# Generated deterministically by seda-macro-lef-normalizer-v1; recipe orfs-asap7-fakeram-m4-v1.
VERSION 5.8 ;
BUSBITCHARS "[]" ;
DIVIDERCHAR "/" ;

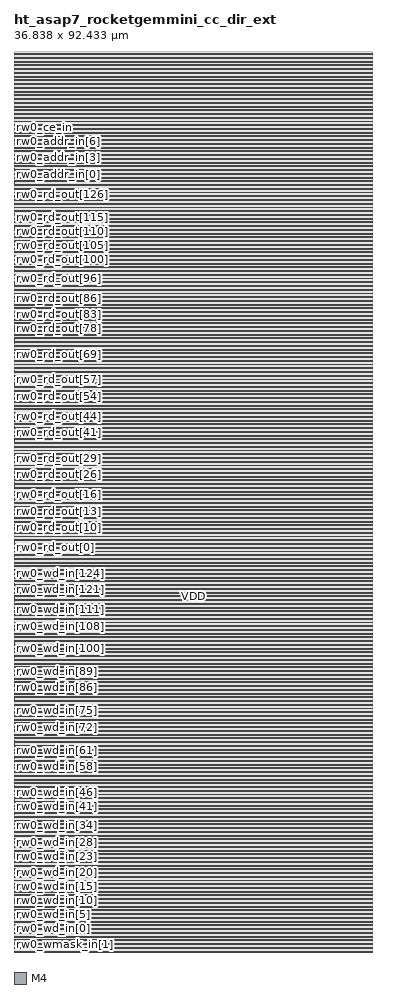
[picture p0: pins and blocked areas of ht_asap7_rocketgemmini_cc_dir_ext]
MACRO ht_asap7_rocketgemmini_cc_dir_ext
  FOREIGN ht_asap7_rocketgemmini_cc_dir_ext 0 0 ;
  CLASS BLOCK ;
  ORIGIN 0 0 ;
  SIZE 36.838 BY 92.433 ;
  SYMMETRY X Y R90 ;
  PIN rw0_wmask_in[0]
    DIRECTION INPUT ;
    USE SIGNAL ;
    SHAPE ABUTMENT ;
    PORT
      LAYER M4 ;
      RECT 0 0.048 0.024 0.072 ;
    END
  END rw0_wmask_in[0]
  PIN rw0_wmask_in[1]
    DIRECTION INPUT ;
    USE SIGNAL ;
    SHAPE ABUTMENT ;
    PORT
      LAYER M4 ;
      RECT 0 0.336 0.024 0.36 ;
    END
  END rw0_wmask_in[1]
  PIN rw0_wmask_in[2]
    DIRECTION INPUT ;
    USE SIGNAL ;
    SHAPE ABUTMENT ;
    PORT
      LAYER M4 ;
      RECT 0 0.624 0.024 0.648 ;
    END
  END rw0_wmask_in[2]
  PIN rw0_wmask_in[3]
    DIRECTION INPUT ;
    USE SIGNAL ;
    SHAPE ABUTMENT ;
    PORT
      LAYER M4 ;
      RECT 0 0.912 0.024 0.936 ;
    END
  END rw0_wmask_in[3]
  PIN rw0_wmask_in[4]
    DIRECTION INPUT ;
    USE SIGNAL ;
    SHAPE ABUTMENT ;
    PORT
      LAYER M4 ;
      RECT 0 1.2 0.024 1.224 ;
    END
  END rw0_wmask_in[4]
  PIN rw0_wmask_in[5]
    DIRECTION INPUT ;
    USE SIGNAL ;
    SHAPE ABUTMENT ;
    PORT
      LAYER M4 ;
      RECT 0 1.488 0.024 1.512 ;
    END
  END rw0_wmask_in[5]
  PIN rw0_wmask_in[6]
    DIRECTION INPUT ;
    USE SIGNAL ;
    SHAPE ABUTMENT ;
    PORT
      LAYER M4 ;
      RECT 0 1.776 0.024 1.8 ;
    END
  END rw0_wmask_in[6]
  PIN rw0_wmask_in[7]
    DIRECTION INPUT ;
    USE SIGNAL ;
    SHAPE ABUTMENT ;
    PORT
      LAYER M4 ;
      RECT 0 2.064 0.024 2.088 ;
    END
  END rw0_wmask_in[7]
  PIN rw0_wd_in[0]
    DIRECTION INPUT ;
    USE SIGNAL ;
    SHAPE ABUTMENT ;
    PORT
      LAYER M4 ;
      RECT 0 2.352 0.024 2.376 ;
    END
  END rw0_wd_in[0]
  PIN rw0_wd_in[1]
    DIRECTION INPUT ;
    USE SIGNAL ;
    SHAPE ABUTMENT ;
    PORT
      LAYER M4 ;
      RECT 0 2.64 0.024 2.664 ;
    END
  END rw0_wd_in[1]
  PIN rw0_wd_in[2]
    DIRECTION INPUT ;
    USE SIGNAL ;
    SHAPE ABUTMENT ;
    PORT
      LAYER M4 ;
      RECT 0 2.928 0.024 2.952 ;
    END
  END rw0_wd_in[2]
  PIN rw0_wd_in[3]
    DIRECTION INPUT ;
    USE SIGNAL ;
    SHAPE ABUTMENT ;
    PORT
      LAYER M4 ;
      RECT 0 3.216 0.024 3.24 ;
    END
  END rw0_wd_in[3]
  PIN rw0_wd_in[4]
    DIRECTION INPUT ;
    USE SIGNAL ;
    SHAPE ABUTMENT ;
    PORT
      LAYER M4 ;
      RECT 0 3.504 0.024 3.528 ;
    END
  END rw0_wd_in[4]
  PIN rw0_wd_in[5]
    DIRECTION INPUT ;
    USE SIGNAL ;
    SHAPE ABUTMENT ;
    PORT
      LAYER M4 ;
      RECT 0 3.792 0.024 3.816 ;
    END
  END rw0_wd_in[5]
  PIN rw0_wd_in[6]
    DIRECTION INPUT ;
    USE SIGNAL ;
    SHAPE ABUTMENT ;
    PORT
      LAYER M4 ;
      RECT 0 4.08 0.024 4.104 ;
    END
  END rw0_wd_in[6]
  PIN rw0_wd_in[7]
    DIRECTION INPUT ;
    USE SIGNAL ;
    SHAPE ABUTMENT ;
    PORT
      LAYER M4 ;
      RECT 0 4.368 0.024 4.392 ;
    END
  END rw0_wd_in[7]
  PIN rw0_wd_in[8]
    DIRECTION INPUT ;
    USE SIGNAL ;
    SHAPE ABUTMENT ;
    PORT
      LAYER M4 ;
      RECT 0 4.656 0.024 4.68 ;
    END
  END rw0_wd_in[8]
  PIN rw0_wd_in[9]
    DIRECTION INPUT ;
    USE SIGNAL ;
    SHAPE ABUTMENT ;
    PORT
      LAYER M4 ;
      RECT 0 4.944 0.024 4.968 ;
    END
  END rw0_wd_in[9]
  PIN rw0_wd_in[10]
    DIRECTION INPUT ;
    USE SIGNAL ;
    SHAPE ABUTMENT ;
    PORT
      LAYER M4 ;
      RECT 0 5.232 0.024 5.256 ;
    END
  END rw0_wd_in[10]
  PIN rw0_wd_in[11]
    DIRECTION INPUT ;
    USE SIGNAL ;
    SHAPE ABUTMENT ;
    PORT
      LAYER M4 ;
      RECT 0 5.52 0.024 5.544 ;
    END
  END rw0_wd_in[11]
  PIN rw0_wd_in[12]
    DIRECTION INPUT ;
    USE SIGNAL ;
    SHAPE ABUTMENT ;
    PORT
      LAYER M4 ;
      RECT 0 5.808 0.024 5.832 ;
    END
  END rw0_wd_in[12]
  PIN rw0_wd_in[13]
    DIRECTION INPUT ;
    USE SIGNAL ;
    SHAPE ABUTMENT ;
    PORT
      LAYER M4 ;
      RECT 0 6.096 0.024 6.12 ;
    END
  END rw0_wd_in[13]
  PIN rw0_wd_in[14]
    DIRECTION INPUT ;
    USE SIGNAL ;
    SHAPE ABUTMENT ;
    PORT
      LAYER M4 ;
      RECT 0 6.384 0.024 6.408 ;
    END
  END rw0_wd_in[14]
  PIN rw0_wd_in[15]
    DIRECTION INPUT ;
    USE SIGNAL ;
    SHAPE ABUTMENT ;
    PORT
      LAYER M4 ;
      RECT 0 6.672 0.024 6.696 ;
    END
  END rw0_wd_in[15]
  PIN rw0_wd_in[16]
    DIRECTION INPUT ;
    USE SIGNAL ;
    SHAPE ABUTMENT ;
    PORT
      LAYER M4 ;
      RECT 0 6.96 0.024 6.984 ;
    END
  END rw0_wd_in[16]
  PIN rw0_wd_in[17]
    DIRECTION INPUT ;
    USE SIGNAL ;
    SHAPE ABUTMENT ;
    PORT
      LAYER M4 ;
      RECT 0 7.248 0.024 7.272 ;
    END
  END rw0_wd_in[17]
  PIN rw0_wd_in[18]
    DIRECTION INPUT ;
    USE SIGNAL ;
    SHAPE ABUTMENT ;
    PORT
      LAYER M4 ;
      RECT 0 7.536 0.024 7.56 ;
    END
  END rw0_wd_in[18]
  PIN rw0_wd_in[19]
    DIRECTION INPUT ;
    USE SIGNAL ;
    SHAPE ABUTMENT ;
    PORT
      LAYER M4 ;
      RECT 0 7.824 0.024 7.848 ;
    END
  END rw0_wd_in[19]
  PIN rw0_wd_in[20]
    DIRECTION INPUT ;
    USE SIGNAL ;
    SHAPE ABUTMENT ;
    PORT
      LAYER M4 ;
      RECT 0 8.112 0.024 8.136 ;
    END
  END rw0_wd_in[20]
  PIN rw0_wd_in[21]
    DIRECTION INPUT ;
    USE SIGNAL ;
    SHAPE ABUTMENT ;
    PORT
      LAYER M4 ;
      RECT 0 8.4 0.024 8.424 ;
    END
  END rw0_wd_in[21]
  PIN rw0_wd_in[22]
    DIRECTION INPUT ;
    USE SIGNAL ;
    SHAPE ABUTMENT ;
    PORT
      LAYER M4 ;
      RECT 0 8.688 0.024 8.712 ;
    END
  END rw0_wd_in[22]
  PIN rw0_wd_in[23]
    DIRECTION INPUT ;
    USE SIGNAL ;
    SHAPE ABUTMENT ;
    PORT
      LAYER M4 ;
      RECT 0 8.976 0.024 9 ;
    END
  END rw0_wd_in[23]
  PIN rw0_wd_in[24]
    DIRECTION INPUT ;
    USE SIGNAL ;
    SHAPE ABUTMENT ;
    PORT
      LAYER M4 ;
      RECT 0 9.264 0.024 9.288 ;
    END
  END rw0_wd_in[24]
  PIN rw0_wd_in[25]
    DIRECTION INPUT ;
    USE SIGNAL ;
    SHAPE ABUTMENT ;
    PORT
      LAYER M4 ;
      RECT 0 9.552 0.024 9.576 ;
    END
  END rw0_wd_in[25]
  PIN rw0_wd_in[26]
    DIRECTION INPUT ;
    USE SIGNAL ;
    SHAPE ABUTMENT ;
    PORT
      LAYER M4 ;
      RECT 0 9.84 0.024 9.864 ;
    END
  END rw0_wd_in[26]
  PIN rw0_wd_in[27]
    DIRECTION INPUT ;
    USE SIGNAL ;
    SHAPE ABUTMENT ;
    PORT
      LAYER M4 ;
      RECT 0 10.128 0.024 10.152 ;
    END
  END rw0_wd_in[27]
  PIN rw0_wd_in[28]
    DIRECTION INPUT ;
    USE SIGNAL ;
    SHAPE ABUTMENT ;
    PORT
      LAYER M4 ;
      RECT 0 10.416 0.024 10.44 ;
    END
  END rw0_wd_in[28]
  PIN rw0_wd_in[29]
    DIRECTION INPUT ;
    USE SIGNAL ;
    SHAPE ABUTMENT ;
    PORT
      LAYER M4 ;
      RECT 0 10.704 0.024 10.728 ;
    END
  END rw0_wd_in[29]
  PIN rw0_wd_in[30]
    DIRECTION INPUT ;
    USE SIGNAL ;
    SHAPE ABUTMENT ;
    PORT
      LAYER M4 ;
      RECT 0 10.992 0.024 11.016 ;
    END
  END rw0_wd_in[30]
  PIN rw0_wd_in[31]
    DIRECTION INPUT ;
    USE SIGNAL ;
    SHAPE ABUTMENT ;
    PORT
      LAYER M4 ;
      RECT 0 11.28 0.024 11.304 ;
    END
  END rw0_wd_in[31]
  PIN rw0_wd_in[32]
    DIRECTION INPUT ;
    USE SIGNAL ;
    SHAPE ABUTMENT ;
    PORT
      LAYER M4 ;
      RECT 0 11.568 0.024 11.592 ;
    END
  END rw0_wd_in[32]
  PIN rw0_wd_in[33]
    DIRECTION INPUT ;
    USE SIGNAL ;
    SHAPE ABUTMENT ;
    PORT
      LAYER M4 ;
      RECT 0 11.856 0.024 11.88 ;
    END
  END rw0_wd_in[33]
  PIN rw0_wd_in[34]
    DIRECTION INPUT ;
    USE SIGNAL ;
    SHAPE ABUTMENT ;
    PORT
      LAYER M4 ;
      RECT 0 12.144 0.024 12.168 ;
    END
  END rw0_wd_in[34]
  PIN rw0_wd_in[35]
    DIRECTION INPUT ;
    USE SIGNAL ;
    SHAPE ABUTMENT ;
    PORT
      LAYER M4 ;
      RECT 0 12.432 0.024 12.456 ;
    END
  END rw0_wd_in[35]
  PIN rw0_wd_in[36]
    DIRECTION INPUT ;
    USE SIGNAL ;
    SHAPE ABUTMENT ;
    PORT
      LAYER M4 ;
      RECT 0 12.72 0.024 12.744 ;
    END
  END rw0_wd_in[36]
  PIN rw0_wd_in[37]
    DIRECTION INPUT ;
    USE SIGNAL ;
    SHAPE ABUTMENT ;
    PORT
      LAYER M4 ;
      RECT 0 13.008 0.024 13.032 ;
    END
  END rw0_wd_in[37]
  PIN rw0_wd_in[38]
    DIRECTION INPUT ;
    USE SIGNAL ;
    SHAPE ABUTMENT ;
    PORT
      LAYER M4 ;
      RECT 0 13.296 0.024 13.32 ;
    END
  END rw0_wd_in[38]
  PIN rw0_wd_in[39]
    DIRECTION INPUT ;
    USE SIGNAL ;
    SHAPE ABUTMENT ;
    PORT
      LAYER M4 ;
      RECT 0 13.584 0.024 13.608 ;
    END
  END rw0_wd_in[39]
  PIN rw0_wd_in[40]
    DIRECTION INPUT ;
    USE SIGNAL ;
    SHAPE ABUTMENT ;
    PORT
      LAYER M4 ;
      RECT 0 13.872 0.024 13.896 ;
    END
  END rw0_wd_in[40]
  PIN rw0_wd_in[41]
    DIRECTION INPUT ;
    USE SIGNAL ;
    SHAPE ABUTMENT ;
    PORT
      LAYER M4 ;
      RECT 0 14.16 0.024 14.184 ;
    END
  END rw0_wd_in[41]
  PIN rw0_wd_in[42]
    DIRECTION INPUT ;
    USE SIGNAL ;
    SHAPE ABUTMENT ;
    PORT
      LAYER M4 ;
      RECT 0 14.448 0.024 14.472 ;
    END
  END rw0_wd_in[42]
  PIN rw0_wd_in[43]
    DIRECTION INPUT ;
    USE SIGNAL ;
    SHAPE ABUTMENT ;
    PORT
      LAYER M4 ;
      RECT 0 14.736 0.024 14.76 ;
    END
  END rw0_wd_in[43]
  PIN rw0_wd_in[44]
    DIRECTION INPUT ;
    USE SIGNAL ;
    SHAPE ABUTMENT ;
    PORT
      LAYER M4 ;
      RECT 0 15.024 0.024 15.048 ;
    END
  END rw0_wd_in[44]
  PIN rw0_wd_in[45]
    DIRECTION INPUT ;
    USE SIGNAL ;
    SHAPE ABUTMENT ;
    PORT
      LAYER M4 ;
      RECT 0 15.312 0.024 15.336 ;
    END
  END rw0_wd_in[45]
  PIN rw0_wd_in[46]
    DIRECTION INPUT ;
    USE SIGNAL ;
    SHAPE ABUTMENT ;
    PORT
      LAYER M4 ;
      RECT 0 15.6 0.024 15.624 ;
    END
  END rw0_wd_in[46]
  PIN rw0_wd_in[47]
    DIRECTION INPUT ;
    USE SIGNAL ;
    SHAPE ABUTMENT ;
    PORT
      LAYER M4 ;
      RECT 0 15.888 0.024 15.912 ;
    END
  END rw0_wd_in[47]
  PIN rw0_wd_in[48]
    DIRECTION INPUT ;
    USE SIGNAL ;
    SHAPE ABUTMENT ;
    PORT
      LAYER M4 ;
      RECT 0 16.176 0.024 16.2 ;
    END
  END rw0_wd_in[48]
  PIN rw0_wd_in[49]
    DIRECTION INPUT ;
    USE SIGNAL ;
    SHAPE ABUTMENT ;
    PORT
      LAYER M4 ;
      RECT 0 16.464 0.024 16.488 ;
    END
  END rw0_wd_in[49]
  PIN rw0_wd_in[50]
    DIRECTION INPUT ;
    USE SIGNAL ;
    SHAPE ABUTMENT ;
    PORT
      LAYER M4 ;
      RECT 0 16.752 0.024 16.776 ;
    END
  END rw0_wd_in[50]
  PIN rw0_wd_in[51]
    DIRECTION INPUT ;
    USE SIGNAL ;
    SHAPE ABUTMENT ;
    PORT
      LAYER M4 ;
      RECT 0 17.04 0.024 17.064 ;
    END
  END rw0_wd_in[51]
  PIN rw0_wd_in[52]
    DIRECTION INPUT ;
    USE SIGNAL ;
    SHAPE ABUTMENT ;
    PORT
      LAYER M4 ;
      RECT 0 17.328 0.024 17.352 ;
    END
  END rw0_wd_in[52]
  PIN rw0_wd_in[53]
    DIRECTION INPUT ;
    USE SIGNAL ;
    SHAPE ABUTMENT ;
    PORT
      LAYER M4 ;
      RECT 0 17.616 0.024 17.64 ;
    END
  END rw0_wd_in[53]
  PIN rw0_wd_in[54]
    DIRECTION INPUT ;
    USE SIGNAL ;
    SHAPE ABUTMENT ;
    PORT
      LAYER M4 ;
      RECT 0 17.904 0.024 17.928 ;
    END
  END rw0_wd_in[54]
  PIN rw0_wd_in[55]
    DIRECTION INPUT ;
    USE SIGNAL ;
    SHAPE ABUTMENT ;
    PORT
      LAYER M4 ;
      RECT 0 18.192 0.024 18.216 ;
    END
  END rw0_wd_in[55]
  PIN rw0_wd_in[56]
    DIRECTION INPUT ;
    USE SIGNAL ;
    SHAPE ABUTMENT ;
    PORT
      LAYER M4 ;
      RECT 0 18.48 0.024 18.504 ;
    END
  END rw0_wd_in[56]
  PIN rw0_wd_in[57]
    DIRECTION INPUT ;
    USE SIGNAL ;
    SHAPE ABUTMENT ;
    PORT
      LAYER M4 ;
      RECT 0 18.768 0.024 18.792 ;
    END
  END rw0_wd_in[57]
  PIN rw0_wd_in[58]
    DIRECTION INPUT ;
    USE SIGNAL ;
    SHAPE ABUTMENT ;
    PORT
      LAYER M4 ;
      RECT 0 19.056 0.024 19.08 ;
    END
  END rw0_wd_in[58]
  PIN rw0_wd_in[59]
    DIRECTION INPUT ;
    USE SIGNAL ;
    SHAPE ABUTMENT ;
    PORT
      LAYER M4 ;
      RECT 0 19.344 0.024 19.368 ;
    END
  END rw0_wd_in[59]
  PIN rw0_wd_in[60]
    DIRECTION INPUT ;
    USE SIGNAL ;
    SHAPE ABUTMENT ;
    PORT
      LAYER M4 ;
      RECT 0 19.632 0.024 19.656 ;
    END
  END rw0_wd_in[60]
  PIN rw0_wd_in[61]
    DIRECTION INPUT ;
    USE SIGNAL ;
    SHAPE ABUTMENT ;
    PORT
      LAYER M4 ;
      RECT 0 19.92 0.024 19.944 ;
    END
  END rw0_wd_in[61]
  PIN rw0_wd_in[62]
    DIRECTION INPUT ;
    USE SIGNAL ;
    SHAPE ABUTMENT ;
    PORT
      LAYER M4 ;
      RECT 0 20.208 0.024 20.232 ;
    END
  END rw0_wd_in[62]
  PIN rw0_wd_in[63]
    DIRECTION INPUT ;
    USE SIGNAL ;
    SHAPE ABUTMENT ;
    PORT
      LAYER M4 ;
      RECT 0 20.496 0.024 20.52 ;
    END
  END rw0_wd_in[63]
  PIN rw0_wd_in[64]
    DIRECTION INPUT ;
    USE SIGNAL ;
    SHAPE ABUTMENT ;
    PORT
      LAYER M4 ;
      RECT 0 20.784 0.024 20.808 ;
    END
  END rw0_wd_in[64]
  PIN rw0_wd_in[65]
    DIRECTION INPUT ;
    USE SIGNAL ;
    SHAPE ABUTMENT ;
    PORT
      LAYER M4 ;
      RECT 0 21.072 0.024 21.096 ;
    END
  END rw0_wd_in[65]
  PIN rw0_wd_in[66]
    DIRECTION INPUT ;
    USE SIGNAL ;
    SHAPE ABUTMENT ;
    PORT
      LAYER M4 ;
      RECT 0 21.36 0.024 21.384 ;
    END
  END rw0_wd_in[66]
  PIN rw0_wd_in[67]
    DIRECTION INPUT ;
    USE SIGNAL ;
    SHAPE ABUTMENT ;
    PORT
      LAYER M4 ;
      RECT 0 21.648 0.024 21.672 ;
    END
  END rw0_wd_in[67]
  PIN rw0_wd_in[68]
    DIRECTION INPUT ;
    USE SIGNAL ;
    SHAPE ABUTMENT ;
    PORT
      LAYER M4 ;
      RECT 0 21.936 0.024 21.96 ;
    END
  END rw0_wd_in[68]
  PIN rw0_wd_in[69]
    DIRECTION INPUT ;
    USE SIGNAL ;
    SHAPE ABUTMENT ;
    PORT
      LAYER M4 ;
      RECT 0 22.224 0.024 22.248 ;
    END
  END rw0_wd_in[69]
  PIN rw0_wd_in[70]
    DIRECTION INPUT ;
    USE SIGNAL ;
    SHAPE ABUTMENT ;
    PORT
      LAYER M4 ;
      RECT 0 22.512 0.024 22.536 ;
    END
  END rw0_wd_in[70]
  PIN rw0_wd_in[71]
    DIRECTION INPUT ;
    USE SIGNAL ;
    SHAPE ABUTMENT ;
    PORT
      LAYER M4 ;
      RECT 0 22.8 0.024 22.824 ;
    END
  END rw0_wd_in[71]
  PIN rw0_wd_in[72]
    DIRECTION INPUT ;
    USE SIGNAL ;
    SHAPE ABUTMENT ;
    PORT
      LAYER M4 ;
      RECT 0 23.088 0.024 23.112 ;
    END
  END rw0_wd_in[72]
  PIN rw0_wd_in[73]
    DIRECTION INPUT ;
    USE SIGNAL ;
    SHAPE ABUTMENT ;
    PORT
      LAYER M4 ;
      RECT 0 23.376 0.024 23.4 ;
    END
  END rw0_wd_in[73]
  PIN rw0_wd_in[74]
    DIRECTION INPUT ;
    USE SIGNAL ;
    SHAPE ABUTMENT ;
    PORT
      LAYER M4 ;
      RECT 0 23.664 0.024 23.688 ;
    END
  END rw0_wd_in[74]
  PIN rw0_wd_in[75]
    DIRECTION INPUT ;
    USE SIGNAL ;
    SHAPE ABUTMENT ;
    PORT
      LAYER M4 ;
      RECT 0 23.952 0.024 23.976 ;
    END
  END rw0_wd_in[75]
  PIN rw0_wd_in[76]
    DIRECTION INPUT ;
    USE SIGNAL ;
    SHAPE ABUTMENT ;
    PORT
      LAYER M4 ;
      RECT 0 24.24 0.024 24.264 ;
    END
  END rw0_wd_in[76]
  PIN rw0_wd_in[77]
    DIRECTION INPUT ;
    USE SIGNAL ;
    SHAPE ABUTMENT ;
    PORT
      LAYER M4 ;
      RECT 0 24.528 0.024 24.552 ;
    END
  END rw0_wd_in[77]
  PIN rw0_wd_in[78]
    DIRECTION INPUT ;
    USE SIGNAL ;
    SHAPE ABUTMENT ;
    PORT
      LAYER M4 ;
      RECT 0 24.816 0.024 24.84 ;
    END
  END rw0_wd_in[78]
  PIN rw0_wd_in[79]
    DIRECTION INPUT ;
    USE SIGNAL ;
    SHAPE ABUTMENT ;
    PORT
      LAYER M4 ;
      RECT 0 25.104 0.024 25.128 ;
    END
  END rw0_wd_in[79]
  PIN rw0_wd_in[80]
    DIRECTION INPUT ;
    USE SIGNAL ;
    SHAPE ABUTMENT ;
    PORT
      LAYER M4 ;
      RECT 0 25.392 0.024 25.416 ;
    END
  END rw0_wd_in[80]
  PIN rw0_wd_in[81]
    DIRECTION INPUT ;
    USE SIGNAL ;
    SHAPE ABUTMENT ;
    PORT
      LAYER M4 ;
      RECT 0 25.68 0.024 25.704 ;
    END
  END rw0_wd_in[81]
  PIN rw0_wd_in[82]
    DIRECTION INPUT ;
    USE SIGNAL ;
    SHAPE ABUTMENT ;
    PORT
      LAYER M4 ;
      RECT 0 25.968 0.024 25.992 ;
    END
  END rw0_wd_in[82]
  PIN rw0_wd_in[83]
    DIRECTION INPUT ;
    USE SIGNAL ;
    SHAPE ABUTMENT ;
    PORT
      LAYER M4 ;
      RECT 0 26.256 0.024 26.28 ;
    END
  END rw0_wd_in[83]
  PIN rw0_wd_in[84]
    DIRECTION INPUT ;
    USE SIGNAL ;
    SHAPE ABUTMENT ;
    PORT
      LAYER M4 ;
      RECT 0 26.544 0.024 26.568 ;
    END
  END rw0_wd_in[84]
  PIN rw0_wd_in[85]
    DIRECTION INPUT ;
    USE SIGNAL ;
    SHAPE ABUTMENT ;
    PORT
      LAYER M4 ;
      RECT 0 26.832 0.024 26.856 ;
    END
  END rw0_wd_in[85]
  PIN rw0_wd_in[86]
    DIRECTION INPUT ;
    USE SIGNAL ;
    SHAPE ABUTMENT ;
    PORT
      LAYER M4 ;
      RECT 0 27.12 0.024 27.144 ;
    END
  END rw0_wd_in[86]
  PIN rw0_wd_in[87]
    DIRECTION INPUT ;
    USE SIGNAL ;
    SHAPE ABUTMENT ;
    PORT
      LAYER M4 ;
      RECT 0 27.408 0.024 27.432 ;
    END
  END rw0_wd_in[87]
  PIN rw0_wd_in[88]
    DIRECTION INPUT ;
    USE SIGNAL ;
    SHAPE ABUTMENT ;
    PORT
      LAYER M4 ;
      RECT 0 27.696 0.024 27.72 ;
    END
  END rw0_wd_in[88]
  PIN rw0_wd_in[89]
    DIRECTION INPUT ;
    USE SIGNAL ;
    SHAPE ABUTMENT ;
    PORT
      LAYER M4 ;
      RECT 0 27.984 0.024 28.008 ;
    END
  END rw0_wd_in[89]
  PIN rw0_wd_in[90]
    DIRECTION INPUT ;
    USE SIGNAL ;
    SHAPE ABUTMENT ;
    PORT
      LAYER M4 ;
      RECT 0 28.272 0.024 28.296 ;
    END
  END rw0_wd_in[90]
  PIN rw0_wd_in[91]
    DIRECTION INPUT ;
    USE SIGNAL ;
    SHAPE ABUTMENT ;
    PORT
      LAYER M4 ;
      RECT 0 28.56 0.024 28.584 ;
    END
  END rw0_wd_in[91]
  PIN rw0_wd_in[92]
    DIRECTION INPUT ;
    USE SIGNAL ;
    SHAPE ABUTMENT ;
    PORT
      LAYER M4 ;
      RECT 0 28.848 0.024 28.872 ;
    END
  END rw0_wd_in[92]
  PIN rw0_wd_in[93]
    DIRECTION INPUT ;
    USE SIGNAL ;
    SHAPE ABUTMENT ;
    PORT
      LAYER M4 ;
      RECT 0 29.136 0.024 29.16 ;
    END
  END rw0_wd_in[93]
  PIN rw0_wd_in[94]
    DIRECTION INPUT ;
    USE SIGNAL ;
    SHAPE ABUTMENT ;
    PORT
      LAYER M4 ;
      RECT 0 29.424 0.024 29.448 ;
    END
  END rw0_wd_in[94]
  PIN rw0_wd_in[95]
    DIRECTION INPUT ;
    USE SIGNAL ;
    SHAPE ABUTMENT ;
    PORT
      LAYER M4 ;
      RECT 0 29.712 0.024 29.736 ;
    END
  END rw0_wd_in[95]
  PIN rw0_wd_in[96]
    DIRECTION INPUT ;
    USE SIGNAL ;
    SHAPE ABUTMENT ;
    PORT
      LAYER M4 ;
      RECT 0 30 0.024 30.024 ;
    END
  END rw0_wd_in[96]
  PIN rw0_wd_in[97]
    DIRECTION INPUT ;
    USE SIGNAL ;
    SHAPE ABUTMENT ;
    PORT
      LAYER M4 ;
      RECT 0 30.288 0.024 30.312 ;
    END
  END rw0_wd_in[97]
  PIN rw0_wd_in[98]
    DIRECTION INPUT ;
    USE SIGNAL ;
    SHAPE ABUTMENT ;
    PORT
      LAYER M4 ;
      RECT 0 30.576 0.024 30.6 ;
    END
  END rw0_wd_in[98]
  PIN rw0_wd_in[99]
    DIRECTION INPUT ;
    USE SIGNAL ;
    SHAPE ABUTMENT ;
    PORT
      LAYER M4 ;
      RECT 0 30.864 0.024 30.888 ;
    END
  END rw0_wd_in[99]
  PIN rw0_wd_in[100]
    DIRECTION INPUT ;
    USE SIGNAL ;
    SHAPE ABUTMENT ;
    PORT
      LAYER M4 ;
      RECT 0 31.152 0.024 31.176 ;
    END
  END rw0_wd_in[100]
  PIN rw0_wd_in[101]
    DIRECTION INPUT ;
    USE SIGNAL ;
    SHAPE ABUTMENT ;
    PORT
      LAYER M4 ;
      RECT 0 31.44 0.024 31.464 ;
    END
  END rw0_wd_in[101]
  PIN rw0_wd_in[102]
    DIRECTION INPUT ;
    USE SIGNAL ;
    SHAPE ABUTMENT ;
    PORT
      LAYER M4 ;
      RECT 0 31.728 0.024 31.752 ;
    END
  END rw0_wd_in[102]
  PIN rw0_wd_in[103]
    DIRECTION INPUT ;
    USE SIGNAL ;
    SHAPE ABUTMENT ;
    PORT
      LAYER M4 ;
      RECT 0 32.016 0.024 32.04 ;
    END
  END rw0_wd_in[103]
  PIN rw0_wd_in[104]
    DIRECTION INPUT ;
    USE SIGNAL ;
    SHAPE ABUTMENT ;
    PORT
      LAYER M4 ;
      RECT 0 32.304 0.024 32.328 ;
    END
  END rw0_wd_in[104]
  PIN rw0_wd_in[105]
    DIRECTION INPUT ;
    USE SIGNAL ;
    SHAPE ABUTMENT ;
    PORT
      LAYER M4 ;
      RECT 0 32.592 0.024 32.616 ;
    END
  END rw0_wd_in[105]
  PIN rw0_wd_in[106]
    DIRECTION INPUT ;
    USE SIGNAL ;
    SHAPE ABUTMENT ;
    PORT
      LAYER M4 ;
      RECT 0 32.88 0.024 32.904 ;
    END
  END rw0_wd_in[106]
  PIN rw0_wd_in[107]
    DIRECTION INPUT ;
    USE SIGNAL ;
    SHAPE ABUTMENT ;
    PORT
      LAYER M4 ;
      RECT 0 33.168 0.024 33.192 ;
    END
  END rw0_wd_in[107]
  PIN rw0_wd_in[108]
    DIRECTION INPUT ;
    USE SIGNAL ;
    SHAPE ABUTMENT ;
    PORT
      LAYER M4 ;
      RECT 0 33.456 0.024 33.48 ;
    END
  END rw0_wd_in[108]
  PIN rw0_wd_in[109]
    DIRECTION INPUT ;
    USE SIGNAL ;
    SHAPE ABUTMENT ;
    PORT
      LAYER M4 ;
      RECT 0 33.744 0.024 33.768 ;
    END
  END rw0_wd_in[109]
  PIN rw0_wd_in[110]
    DIRECTION INPUT ;
    USE SIGNAL ;
    SHAPE ABUTMENT ;
    PORT
      LAYER M4 ;
      RECT 0 34.032 0.024 34.056 ;
    END
  END rw0_wd_in[110]
  PIN rw0_wd_in[111]
    DIRECTION INPUT ;
    USE SIGNAL ;
    SHAPE ABUTMENT ;
    PORT
      LAYER M4 ;
      RECT 0 34.32 0.024 34.344 ;
    END
  END rw0_wd_in[111]
  PIN rw0_wd_in[112]
    DIRECTION INPUT ;
    USE SIGNAL ;
    SHAPE ABUTMENT ;
    PORT
      LAYER M4 ;
      RECT 0 34.608 0.024 34.632 ;
    END
  END rw0_wd_in[112]
  PIN rw0_wd_in[113]
    DIRECTION INPUT ;
    USE SIGNAL ;
    SHAPE ABUTMENT ;
    PORT
      LAYER M4 ;
      RECT 0 34.896 0.024 34.92 ;
    END
  END rw0_wd_in[113]
  PIN rw0_wd_in[114]
    DIRECTION INPUT ;
    USE SIGNAL ;
    SHAPE ABUTMENT ;
    PORT
      LAYER M4 ;
      RECT 0 35.184 0.024 35.208 ;
    END
  END rw0_wd_in[114]
  PIN rw0_wd_in[115]
    DIRECTION INPUT ;
    USE SIGNAL ;
    SHAPE ABUTMENT ;
    PORT
      LAYER M4 ;
      RECT 0 35.472 0.024 35.496 ;
    END
  END rw0_wd_in[115]
  PIN rw0_wd_in[116]
    DIRECTION INPUT ;
    USE SIGNAL ;
    SHAPE ABUTMENT ;
    PORT
      LAYER M4 ;
      RECT 0 35.76 0.024 35.784 ;
    END
  END rw0_wd_in[116]
  PIN rw0_wd_in[117]
    DIRECTION INPUT ;
    USE SIGNAL ;
    SHAPE ABUTMENT ;
    PORT
      LAYER M4 ;
      RECT 0 36.048 0.024 36.072 ;
    END
  END rw0_wd_in[117]
  PIN rw0_wd_in[118]
    DIRECTION INPUT ;
    USE SIGNAL ;
    SHAPE ABUTMENT ;
    PORT
      LAYER M4 ;
      RECT 0 36.336 0.024 36.36 ;
    END
  END rw0_wd_in[118]
  PIN rw0_wd_in[119]
    DIRECTION INPUT ;
    USE SIGNAL ;
    SHAPE ABUTMENT ;
    PORT
      LAYER M4 ;
      RECT 0 36.624 0.024 36.648 ;
    END
  END rw0_wd_in[119]
  PIN rw0_wd_in[120]
    DIRECTION INPUT ;
    USE SIGNAL ;
    SHAPE ABUTMENT ;
    PORT
      LAYER M4 ;
      RECT 0 36.912 0.024 36.936 ;
    END
  END rw0_wd_in[120]
  PIN rw0_wd_in[121]
    DIRECTION INPUT ;
    USE SIGNAL ;
    SHAPE ABUTMENT ;
    PORT
      LAYER M4 ;
      RECT 0 37.2 0.024 37.224 ;
    END
  END rw0_wd_in[121]
  PIN rw0_wd_in[122]
    DIRECTION INPUT ;
    USE SIGNAL ;
    SHAPE ABUTMENT ;
    PORT
      LAYER M4 ;
      RECT 0 37.488 0.024 37.512 ;
    END
  END rw0_wd_in[122]
  PIN rw0_wd_in[123]
    DIRECTION INPUT ;
    USE SIGNAL ;
    SHAPE ABUTMENT ;
    PORT
      LAYER M4 ;
      RECT 0 37.776 0.024 37.8 ;
    END
  END rw0_wd_in[123]
  PIN rw0_wd_in[124]
    DIRECTION INPUT ;
    USE SIGNAL ;
    SHAPE ABUTMENT ;
    PORT
      LAYER M4 ;
      RECT 0 38.064 0.024 38.088 ;
    END
  END rw0_wd_in[124]
  PIN rw0_wd_in[125]
    DIRECTION INPUT ;
    USE SIGNAL ;
    SHAPE ABUTMENT ;
    PORT
      LAYER M4 ;
      RECT 0 38.352 0.024 38.376 ;
    END
  END rw0_wd_in[125]
  PIN rw0_wd_in[126]
    DIRECTION INPUT ;
    USE SIGNAL ;
    SHAPE ABUTMENT ;
    PORT
      LAYER M4 ;
      RECT 0 38.64 0.024 38.664 ;
    END
  END rw0_wd_in[126]
  PIN rw0_wd_in[127]
    DIRECTION INPUT ;
    USE SIGNAL ;
    SHAPE ABUTMENT ;
    PORT
      LAYER M4 ;
      RECT 0 38.928 0.024 38.952 ;
    END
  END rw0_wd_in[127]
  PIN rw0_wd_in[128]
    DIRECTION INPUT ;
    USE SIGNAL ;
    SHAPE ABUTMENT ;
    PORT
      LAYER M4 ;
      RECT 0 39.216 0.024 39.24 ;
    END
  END rw0_wd_in[128]
  PIN rw0_wd_in[129]
    DIRECTION INPUT ;
    USE SIGNAL ;
    SHAPE ABUTMENT ;
    PORT
      LAYER M4 ;
      RECT 0 39.504 0.024 39.528 ;
    END
  END rw0_wd_in[129]
  PIN rw0_wd_in[130]
    DIRECTION INPUT ;
    USE SIGNAL ;
    SHAPE ABUTMENT ;
    PORT
      LAYER M4 ;
      RECT 0 39.792 0.024 39.816 ;
    END
  END rw0_wd_in[130]
  PIN rw0_wd_in[131]
    DIRECTION INPUT ;
    USE SIGNAL ;
    SHAPE ABUTMENT ;
    PORT
      LAYER M4 ;
      RECT 0 40.08 0.024 40.104 ;
    END
  END rw0_wd_in[131]
  PIN rw0_wd_in[132]
    DIRECTION INPUT ;
    USE SIGNAL ;
    SHAPE ABUTMENT ;
    PORT
      LAYER M4 ;
      RECT 0 40.368 0.024 40.392 ;
    END
  END rw0_wd_in[132]
  PIN rw0_wd_in[133]
    DIRECTION INPUT ;
    USE SIGNAL ;
    SHAPE ABUTMENT ;
    PORT
      LAYER M4 ;
      RECT 0 40.656 0.024 40.68 ;
    END
  END rw0_wd_in[133]
  PIN rw0_wd_in[134]
    DIRECTION INPUT ;
    USE SIGNAL ;
    SHAPE ABUTMENT ;
    PORT
      LAYER M4 ;
      RECT 0 40.944 0.024 40.968 ;
    END
  END rw0_wd_in[134]
  PIN rw0_wd_in[135]
    DIRECTION INPUT ;
    USE SIGNAL ;
    SHAPE ABUTMENT ;
    PORT
      LAYER M4 ;
      RECT 0 41.232 0.024 41.256 ;
    END
  END rw0_wd_in[135]
  PIN rw0_rd_out[0]
    DIRECTION OUTPUT ;
    USE SIGNAL ;
    SHAPE ABUTMENT ;
    PORT
      LAYER M4 ;
      RECT 0 41.52 0.024 41.544 ;
    END
  END rw0_rd_out[0]
  PIN rw0_rd_out[1]
    DIRECTION OUTPUT ;
    USE SIGNAL ;
    SHAPE ABUTMENT ;
    PORT
      LAYER M4 ;
      RECT 0 41.808 0.024 41.832 ;
    END
  END rw0_rd_out[1]
  PIN rw0_rd_out[2]
    DIRECTION OUTPUT ;
    USE SIGNAL ;
    SHAPE ABUTMENT ;
    PORT
      LAYER M4 ;
      RECT 0 42.096 0.024 42.12 ;
    END
  END rw0_rd_out[2]
  PIN rw0_rd_out[3]
    DIRECTION OUTPUT ;
    USE SIGNAL ;
    SHAPE ABUTMENT ;
    PORT
      LAYER M4 ;
      RECT 0 42.384 0.024 42.408 ;
    END
  END rw0_rd_out[3]
  PIN rw0_rd_out[4]
    DIRECTION OUTPUT ;
    USE SIGNAL ;
    SHAPE ABUTMENT ;
    PORT
      LAYER M4 ;
      RECT 0 42.672 0.024 42.696 ;
    END
  END rw0_rd_out[4]
  PIN rw0_rd_out[5]
    DIRECTION OUTPUT ;
    USE SIGNAL ;
    SHAPE ABUTMENT ;
    PORT
      LAYER M4 ;
      RECT 0 42.96 0.024 42.984 ;
    END
  END rw0_rd_out[5]
  PIN rw0_rd_out[6]
    DIRECTION OUTPUT ;
    USE SIGNAL ;
    SHAPE ABUTMENT ;
    PORT
      LAYER M4 ;
      RECT 0 43.248 0.024 43.272 ;
    END
  END rw0_rd_out[6]
  PIN rw0_rd_out[7]
    DIRECTION OUTPUT ;
    USE SIGNAL ;
    SHAPE ABUTMENT ;
    PORT
      LAYER M4 ;
      RECT 0 43.536 0.024 43.56 ;
    END
  END rw0_rd_out[7]
  PIN rw0_rd_out[8]
    DIRECTION OUTPUT ;
    USE SIGNAL ;
    SHAPE ABUTMENT ;
    PORT
      LAYER M4 ;
      RECT 0 43.824 0.024 43.848 ;
    END
  END rw0_rd_out[8]
  PIN rw0_rd_out[9]
    DIRECTION OUTPUT ;
    USE SIGNAL ;
    SHAPE ABUTMENT ;
    PORT
      LAYER M4 ;
      RECT 0 44.112 0.024 44.136 ;
    END
  END rw0_rd_out[9]
  PIN rw0_rd_out[10]
    DIRECTION OUTPUT ;
    USE SIGNAL ;
    SHAPE ABUTMENT ;
    PORT
      LAYER M4 ;
      RECT 0 44.4 0.024 44.424 ;
    END
  END rw0_rd_out[10]
  PIN rw0_rd_out[11]
    DIRECTION OUTPUT ;
    USE SIGNAL ;
    SHAPE ABUTMENT ;
    PORT
      LAYER M4 ;
      RECT 0 44.688 0.024 44.712 ;
    END
  END rw0_rd_out[11]
  PIN rw0_rd_out[12]
    DIRECTION OUTPUT ;
    USE SIGNAL ;
    SHAPE ABUTMENT ;
    PORT
      LAYER M4 ;
      RECT 0 44.976 0.024 45 ;
    END
  END rw0_rd_out[12]
  PIN rw0_rd_out[13]
    DIRECTION OUTPUT ;
    USE SIGNAL ;
    SHAPE ABUTMENT ;
    PORT
      LAYER M4 ;
      RECT 0 45.264 0.024 45.288 ;
    END
  END rw0_rd_out[13]
  PIN rw0_rd_out[14]
    DIRECTION OUTPUT ;
    USE SIGNAL ;
    SHAPE ABUTMENT ;
    PORT
      LAYER M4 ;
      RECT 0 45.552 0.024 45.576 ;
    END
  END rw0_rd_out[14]
  PIN rw0_rd_out[15]
    DIRECTION OUTPUT ;
    USE SIGNAL ;
    SHAPE ABUTMENT ;
    PORT
      LAYER M4 ;
      RECT 0 45.84 0.024 45.864 ;
    END
  END rw0_rd_out[15]
  PIN rw0_rd_out[16]
    DIRECTION OUTPUT ;
    USE SIGNAL ;
    SHAPE ABUTMENT ;
    PORT
      LAYER M4 ;
      RECT 0 46.128 0.024 46.152 ;
    END
  END rw0_rd_out[16]
  PIN rw0_rd_out[17]
    DIRECTION OUTPUT ;
    USE SIGNAL ;
    SHAPE ABUTMENT ;
    PORT
      LAYER M4 ;
      RECT 0 46.416 0.024 46.44 ;
    END
  END rw0_rd_out[17]
  PIN rw0_rd_out[18]
    DIRECTION OUTPUT ;
    USE SIGNAL ;
    SHAPE ABUTMENT ;
    PORT
      LAYER M4 ;
      RECT 0 46.704 0.024 46.728 ;
    END
  END rw0_rd_out[18]
  PIN rw0_rd_out[19]
    DIRECTION OUTPUT ;
    USE SIGNAL ;
    SHAPE ABUTMENT ;
    PORT
      LAYER M4 ;
      RECT 0 46.992 0.024 47.016 ;
    END
  END rw0_rd_out[19]
  PIN rw0_rd_out[20]
    DIRECTION OUTPUT ;
    USE SIGNAL ;
    SHAPE ABUTMENT ;
    PORT
      LAYER M4 ;
      RECT 0 47.28 0.024 47.304 ;
    END
  END rw0_rd_out[20]
  PIN rw0_rd_out[21]
    DIRECTION OUTPUT ;
    USE SIGNAL ;
    SHAPE ABUTMENT ;
    PORT
      LAYER M4 ;
      RECT 0 47.568 0.024 47.592 ;
    END
  END rw0_rd_out[21]
  PIN rw0_rd_out[22]
    DIRECTION OUTPUT ;
    USE SIGNAL ;
    SHAPE ABUTMENT ;
    PORT
      LAYER M4 ;
      RECT 0 47.856 0.024 47.88 ;
    END
  END rw0_rd_out[22]
  PIN rw0_rd_out[23]
    DIRECTION OUTPUT ;
    USE SIGNAL ;
    SHAPE ABUTMENT ;
    PORT
      LAYER M4 ;
      RECT 0 48.144 0.024 48.168 ;
    END
  END rw0_rd_out[23]
  PIN rw0_rd_out[24]
    DIRECTION OUTPUT ;
    USE SIGNAL ;
    SHAPE ABUTMENT ;
    PORT
      LAYER M4 ;
      RECT 0 48.432 0.024 48.456 ;
    END
  END rw0_rd_out[24]
  PIN rw0_rd_out[25]
    DIRECTION OUTPUT ;
    USE SIGNAL ;
    SHAPE ABUTMENT ;
    PORT
      LAYER M4 ;
      RECT 0 48.72 0.024 48.744 ;
    END
  END rw0_rd_out[25]
  PIN rw0_rd_out[26]
    DIRECTION OUTPUT ;
    USE SIGNAL ;
    SHAPE ABUTMENT ;
    PORT
      LAYER M4 ;
      RECT 0 49.008 0.024 49.032 ;
    END
  END rw0_rd_out[26]
  PIN rw0_rd_out[27]
    DIRECTION OUTPUT ;
    USE SIGNAL ;
    SHAPE ABUTMENT ;
    PORT
      LAYER M4 ;
      RECT 0 49.296 0.024 49.32 ;
    END
  END rw0_rd_out[27]
  PIN rw0_rd_out[28]
    DIRECTION OUTPUT ;
    USE SIGNAL ;
    SHAPE ABUTMENT ;
    PORT
      LAYER M4 ;
      RECT 0 49.584 0.024 49.608 ;
    END
  END rw0_rd_out[28]
  PIN rw0_rd_out[29]
    DIRECTION OUTPUT ;
    USE SIGNAL ;
    SHAPE ABUTMENT ;
    PORT
      LAYER M4 ;
      RECT 0 49.872 0.024 49.896 ;
    END
  END rw0_rd_out[29]
  PIN rw0_rd_out[30]
    DIRECTION OUTPUT ;
    USE SIGNAL ;
    SHAPE ABUTMENT ;
    PORT
      LAYER M4 ;
      RECT 0 50.16 0.024 50.184 ;
    END
  END rw0_rd_out[30]
  PIN rw0_rd_out[31]
    DIRECTION OUTPUT ;
    USE SIGNAL ;
    SHAPE ABUTMENT ;
    PORT
      LAYER M4 ;
      RECT 0 50.448 0.024 50.472 ;
    END
  END rw0_rd_out[31]
  PIN rw0_rd_out[32]
    DIRECTION OUTPUT ;
    USE SIGNAL ;
    SHAPE ABUTMENT ;
    PORT
      LAYER M4 ;
      RECT 0 50.736 0.024 50.76 ;
    END
  END rw0_rd_out[32]
  PIN rw0_rd_out[33]
    DIRECTION OUTPUT ;
    USE SIGNAL ;
    SHAPE ABUTMENT ;
    PORT
      LAYER M4 ;
      RECT 0 51.024 0.024 51.048 ;
    END
  END rw0_rd_out[33]
  PIN rw0_rd_out[34]
    DIRECTION OUTPUT ;
    USE SIGNAL ;
    SHAPE ABUTMENT ;
    PORT
      LAYER M4 ;
      RECT 0 51.312 0.024 51.336 ;
    END
  END rw0_rd_out[34]
  PIN rw0_rd_out[35]
    DIRECTION OUTPUT ;
    USE SIGNAL ;
    SHAPE ABUTMENT ;
    PORT
      LAYER M4 ;
      RECT 0 51.6 0.024 51.624 ;
    END
  END rw0_rd_out[35]
  PIN rw0_rd_out[36]
    DIRECTION OUTPUT ;
    USE SIGNAL ;
    SHAPE ABUTMENT ;
    PORT
      LAYER M4 ;
      RECT 0 51.888 0.024 51.912 ;
    END
  END rw0_rd_out[36]
  PIN rw0_rd_out[37]
    DIRECTION OUTPUT ;
    USE SIGNAL ;
    SHAPE ABUTMENT ;
    PORT
      LAYER M4 ;
      RECT 0 52.176 0.024 52.2 ;
    END
  END rw0_rd_out[37]
  PIN rw0_rd_out[38]
    DIRECTION OUTPUT ;
    USE SIGNAL ;
    SHAPE ABUTMENT ;
    PORT
      LAYER M4 ;
      RECT 0 52.464 0.024 52.488 ;
    END
  END rw0_rd_out[38]
  PIN rw0_rd_out[39]
    DIRECTION OUTPUT ;
    USE SIGNAL ;
    SHAPE ABUTMENT ;
    PORT
      LAYER M4 ;
      RECT 0 52.752 0.024 52.776 ;
    END
  END rw0_rd_out[39]
  PIN rw0_rd_out[40]
    DIRECTION OUTPUT ;
    USE SIGNAL ;
    SHAPE ABUTMENT ;
    PORT
      LAYER M4 ;
      RECT 0 53.04 0.024 53.064 ;
    END
  END rw0_rd_out[40]
  PIN rw0_rd_out[41]
    DIRECTION OUTPUT ;
    USE SIGNAL ;
    SHAPE ABUTMENT ;
    PORT
      LAYER M4 ;
      RECT 0 53.328 0.024 53.352 ;
    END
  END rw0_rd_out[41]
  PIN rw0_rd_out[42]
    DIRECTION OUTPUT ;
    USE SIGNAL ;
    SHAPE ABUTMENT ;
    PORT
      LAYER M4 ;
      RECT 0 53.616 0.024 53.64 ;
    END
  END rw0_rd_out[42]
  PIN rw0_rd_out[43]
    DIRECTION OUTPUT ;
    USE SIGNAL ;
    SHAPE ABUTMENT ;
    PORT
      LAYER M4 ;
      RECT 0 53.904 0.024 53.928 ;
    END
  END rw0_rd_out[43]
  PIN rw0_rd_out[44]
    DIRECTION OUTPUT ;
    USE SIGNAL ;
    SHAPE ABUTMENT ;
    PORT
      LAYER M4 ;
      RECT 0 54.192 0.024 54.216 ;
    END
  END rw0_rd_out[44]
  PIN rw0_rd_out[45]
    DIRECTION OUTPUT ;
    USE SIGNAL ;
    SHAPE ABUTMENT ;
    PORT
      LAYER M4 ;
      RECT 0 54.48 0.024 54.504 ;
    END
  END rw0_rd_out[45]
  PIN rw0_rd_out[46]
    DIRECTION OUTPUT ;
    USE SIGNAL ;
    SHAPE ABUTMENT ;
    PORT
      LAYER M4 ;
      RECT 0 54.768 0.024 54.792 ;
    END
  END rw0_rd_out[46]
  PIN rw0_rd_out[47]
    DIRECTION OUTPUT ;
    USE SIGNAL ;
    SHAPE ABUTMENT ;
    PORT
      LAYER M4 ;
      RECT 0 55.056 0.024 55.08 ;
    END
  END rw0_rd_out[47]
  PIN rw0_rd_out[48]
    DIRECTION OUTPUT ;
    USE SIGNAL ;
    SHAPE ABUTMENT ;
    PORT
      LAYER M4 ;
      RECT 0 55.344 0.024 55.368 ;
    END
  END rw0_rd_out[48]
  PIN rw0_rd_out[49]
    DIRECTION OUTPUT ;
    USE SIGNAL ;
    SHAPE ABUTMENT ;
    PORT
      LAYER M4 ;
      RECT 0 55.632 0.024 55.656 ;
    END
  END rw0_rd_out[49]
  PIN rw0_rd_out[50]
    DIRECTION OUTPUT ;
    USE SIGNAL ;
    SHAPE ABUTMENT ;
    PORT
      LAYER M4 ;
      RECT 0 55.92 0.024 55.944 ;
    END
  END rw0_rd_out[50]
  PIN rw0_rd_out[51]
    DIRECTION OUTPUT ;
    USE SIGNAL ;
    SHAPE ABUTMENT ;
    PORT
      LAYER M4 ;
      RECT 0 56.208 0.024 56.232 ;
    END
  END rw0_rd_out[51]
  PIN rw0_rd_out[52]
    DIRECTION OUTPUT ;
    USE SIGNAL ;
    SHAPE ABUTMENT ;
    PORT
      LAYER M4 ;
      RECT 0 56.496 0.024 56.52 ;
    END
  END rw0_rd_out[52]
  PIN rw0_rd_out[53]
    DIRECTION OUTPUT ;
    USE SIGNAL ;
    SHAPE ABUTMENT ;
    PORT
      LAYER M4 ;
      RECT 0 56.784 0.024 56.808 ;
    END
  END rw0_rd_out[53]
  PIN rw0_rd_out[54]
    DIRECTION OUTPUT ;
    USE SIGNAL ;
    SHAPE ABUTMENT ;
    PORT
      LAYER M4 ;
      RECT 0 57.072 0.024 57.096 ;
    END
  END rw0_rd_out[54]
  PIN rw0_rd_out[55]
    DIRECTION OUTPUT ;
    USE SIGNAL ;
    SHAPE ABUTMENT ;
    PORT
      LAYER M4 ;
      RECT 0 57.36 0.024 57.384 ;
    END
  END rw0_rd_out[55]
  PIN rw0_rd_out[56]
    DIRECTION OUTPUT ;
    USE SIGNAL ;
    SHAPE ABUTMENT ;
    PORT
      LAYER M4 ;
      RECT 0 57.648 0.024 57.672 ;
    END
  END rw0_rd_out[56]
  PIN rw0_rd_out[57]
    DIRECTION OUTPUT ;
    USE SIGNAL ;
    SHAPE ABUTMENT ;
    PORT
      LAYER M4 ;
      RECT 0 57.936 0.024 57.96 ;
    END
  END rw0_rd_out[57]
  PIN rw0_rd_out[58]
    DIRECTION OUTPUT ;
    USE SIGNAL ;
    SHAPE ABUTMENT ;
    PORT
      LAYER M4 ;
      RECT 0 58.224 0.024 58.248 ;
    END
  END rw0_rd_out[58]
  PIN rw0_rd_out[59]
    DIRECTION OUTPUT ;
    USE SIGNAL ;
    SHAPE ABUTMENT ;
    PORT
      LAYER M4 ;
      RECT 0 58.512 0.024 58.536 ;
    END
  END rw0_rd_out[59]
  PIN rw0_rd_out[60]
    DIRECTION OUTPUT ;
    USE SIGNAL ;
    SHAPE ABUTMENT ;
    PORT
      LAYER M4 ;
      RECT 0 58.8 0.024 58.824 ;
    END
  END rw0_rd_out[60]
  PIN rw0_rd_out[61]
    DIRECTION OUTPUT ;
    USE SIGNAL ;
    SHAPE ABUTMENT ;
    PORT
      LAYER M4 ;
      RECT 0 59.088 0.024 59.112 ;
    END
  END rw0_rd_out[61]
  PIN rw0_rd_out[62]
    DIRECTION OUTPUT ;
    USE SIGNAL ;
    SHAPE ABUTMENT ;
    PORT
      LAYER M4 ;
      RECT 0 59.376 0.024 59.4 ;
    END
  END rw0_rd_out[62]
  PIN rw0_rd_out[63]
    DIRECTION OUTPUT ;
    USE SIGNAL ;
    SHAPE ABUTMENT ;
    PORT
      LAYER M4 ;
      RECT 0 59.664 0.024 59.688 ;
    END
  END rw0_rd_out[63]
  PIN rw0_rd_out[64]
    DIRECTION OUTPUT ;
    USE SIGNAL ;
    SHAPE ABUTMENT ;
    PORT
      LAYER M4 ;
      RECT 0 59.952 0.024 59.976 ;
    END
  END rw0_rd_out[64]
  PIN rw0_rd_out[65]
    DIRECTION OUTPUT ;
    USE SIGNAL ;
    SHAPE ABUTMENT ;
    PORT
      LAYER M4 ;
      RECT 0 60.24 0.024 60.264 ;
    END
  END rw0_rd_out[65]
  PIN rw0_rd_out[66]
    DIRECTION OUTPUT ;
    USE SIGNAL ;
    SHAPE ABUTMENT ;
    PORT
      LAYER M4 ;
      RECT 0 60.528 0.024 60.552 ;
    END
  END rw0_rd_out[66]
  PIN rw0_rd_out[67]
    DIRECTION OUTPUT ;
    USE SIGNAL ;
    SHAPE ABUTMENT ;
    PORT
      LAYER M4 ;
      RECT 0 60.816 0.024 60.84 ;
    END
  END rw0_rd_out[67]
  PIN rw0_rd_out[68]
    DIRECTION OUTPUT ;
    USE SIGNAL ;
    SHAPE ABUTMENT ;
    PORT
      LAYER M4 ;
      RECT 0 61.104 0.024 61.128 ;
    END
  END rw0_rd_out[68]
  PIN rw0_rd_out[69]
    DIRECTION OUTPUT ;
    USE SIGNAL ;
    SHAPE ABUTMENT ;
    PORT
      LAYER M4 ;
      RECT 0 61.392 0.024 61.416 ;
    END
  END rw0_rd_out[69]
  PIN rw0_rd_out[70]
    DIRECTION OUTPUT ;
    USE SIGNAL ;
    SHAPE ABUTMENT ;
    PORT
      LAYER M4 ;
      RECT 0 61.68 0.024 61.704 ;
    END
  END rw0_rd_out[70]
  PIN rw0_rd_out[71]
    DIRECTION OUTPUT ;
    USE SIGNAL ;
    SHAPE ABUTMENT ;
    PORT
      LAYER M4 ;
      RECT 0 61.968 0.024 61.992 ;
    END
  END rw0_rd_out[71]
  PIN rw0_rd_out[72]
    DIRECTION OUTPUT ;
    USE SIGNAL ;
    SHAPE ABUTMENT ;
    PORT
      LAYER M4 ;
      RECT 0 62.256 0.024 62.28 ;
    END
  END rw0_rd_out[72]
  PIN rw0_rd_out[73]
    DIRECTION OUTPUT ;
    USE SIGNAL ;
    SHAPE ABUTMENT ;
    PORT
      LAYER M4 ;
      RECT 0 62.544 0.024 62.568 ;
    END
  END rw0_rd_out[73]
  PIN rw0_rd_out[74]
    DIRECTION OUTPUT ;
    USE SIGNAL ;
    SHAPE ABUTMENT ;
    PORT
      LAYER M4 ;
      RECT 0 62.832 0.024 62.856 ;
    END
  END rw0_rd_out[74]
  PIN rw0_rd_out[75]
    DIRECTION OUTPUT ;
    USE SIGNAL ;
    SHAPE ABUTMENT ;
    PORT
      LAYER M4 ;
      RECT 0 63.12 0.024 63.144 ;
    END
  END rw0_rd_out[75]
  PIN rw0_rd_out[76]
    DIRECTION OUTPUT ;
    USE SIGNAL ;
    SHAPE ABUTMENT ;
    PORT
      LAYER M4 ;
      RECT 0 63.408 0.024 63.432 ;
    END
  END rw0_rd_out[76]
  PIN rw0_rd_out[77]
    DIRECTION OUTPUT ;
    USE SIGNAL ;
    SHAPE ABUTMENT ;
    PORT
      LAYER M4 ;
      RECT 0 63.696 0.024 63.72 ;
    END
  END rw0_rd_out[77]
  PIN rw0_rd_out[78]
    DIRECTION OUTPUT ;
    USE SIGNAL ;
    SHAPE ABUTMENT ;
    PORT
      LAYER M4 ;
      RECT 0 63.984 0.024 64.008 ;
    END
  END rw0_rd_out[78]
  PIN rw0_rd_out[79]
    DIRECTION OUTPUT ;
    USE SIGNAL ;
    SHAPE ABUTMENT ;
    PORT
      LAYER M4 ;
      RECT 0 64.272 0.024 64.296 ;
    END
  END rw0_rd_out[79]
  PIN rw0_rd_out[80]
    DIRECTION OUTPUT ;
    USE SIGNAL ;
    SHAPE ABUTMENT ;
    PORT
      LAYER M4 ;
      RECT 0 64.56 0.024 64.584 ;
    END
  END rw0_rd_out[80]
  PIN rw0_rd_out[81]
    DIRECTION OUTPUT ;
    USE SIGNAL ;
    SHAPE ABUTMENT ;
    PORT
      LAYER M4 ;
      RECT 0 64.848 0.024 64.872 ;
    END
  END rw0_rd_out[81]
  PIN rw0_rd_out[82]
    DIRECTION OUTPUT ;
    USE SIGNAL ;
    SHAPE ABUTMENT ;
    PORT
      LAYER M4 ;
      RECT 0 65.136 0.024 65.16 ;
    END
  END rw0_rd_out[82]
  PIN rw0_rd_out[83]
    DIRECTION OUTPUT ;
    USE SIGNAL ;
    SHAPE ABUTMENT ;
    PORT
      LAYER M4 ;
      RECT 0 65.424 0.024 65.448 ;
    END
  END rw0_rd_out[83]
  PIN rw0_rd_out[84]
    DIRECTION OUTPUT ;
    USE SIGNAL ;
    SHAPE ABUTMENT ;
    PORT
      LAYER M4 ;
      RECT 0 65.712 0.024 65.736 ;
    END
  END rw0_rd_out[84]
  PIN rw0_rd_out[85]
    DIRECTION OUTPUT ;
    USE SIGNAL ;
    SHAPE ABUTMENT ;
    PORT
      LAYER M4 ;
      RECT 0 66 0.024 66.024 ;
    END
  END rw0_rd_out[85]
  PIN rw0_rd_out[86]
    DIRECTION OUTPUT ;
    USE SIGNAL ;
    SHAPE ABUTMENT ;
    PORT
      LAYER M4 ;
      RECT 0 66.288 0.024 66.312 ;
    END
  END rw0_rd_out[86]
  PIN rw0_rd_out[87]
    DIRECTION OUTPUT ;
    USE SIGNAL ;
    SHAPE ABUTMENT ;
    PORT
      LAYER M4 ;
      RECT 0 66.576 0.024 66.6 ;
    END
  END rw0_rd_out[87]
  PIN rw0_rd_out[88]
    DIRECTION OUTPUT ;
    USE SIGNAL ;
    SHAPE ABUTMENT ;
    PORT
      LAYER M4 ;
      RECT 0 66.864 0.024 66.888 ;
    END
  END rw0_rd_out[88]
  PIN rw0_rd_out[89]
    DIRECTION OUTPUT ;
    USE SIGNAL ;
    SHAPE ABUTMENT ;
    PORT
      LAYER M4 ;
      RECT 0 67.152 0.024 67.176 ;
    END
  END rw0_rd_out[89]
  PIN rw0_rd_out[90]
    DIRECTION OUTPUT ;
    USE SIGNAL ;
    SHAPE ABUTMENT ;
    PORT
      LAYER M4 ;
      RECT 0 67.44 0.024 67.464 ;
    END
  END rw0_rd_out[90]
  PIN rw0_rd_out[91]
    DIRECTION OUTPUT ;
    USE SIGNAL ;
    SHAPE ABUTMENT ;
    PORT
      LAYER M4 ;
      RECT 0 67.728 0.024 67.752 ;
    END
  END rw0_rd_out[91]
  PIN rw0_rd_out[92]
    DIRECTION OUTPUT ;
    USE SIGNAL ;
    SHAPE ABUTMENT ;
    PORT
      LAYER M4 ;
      RECT 0 68.016 0.024 68.04 ;
    END
  END rw0_rd_out[92]
  PIN rw0_rd_out[93]
    DIRECTION OUTPUT ;
    USE SIGNAL ;
    SHAPE ABUTMENT ;
    PORT
      LAYER M4 ;
      RECT 0 68.304 0.024 68.328 ;
    END
  END rw0_rd_out[93]
  PIN rw0_rd_out[94]
    DIRECTION OUTPUT ;
    USE SIGNAL ;
    SHAPE ABUTMENT ;
    PORT
      LAYER M4 ;
      RECT 0 68.592 0.024 68.616 ;
    END
  END rw0_rd_out[94]
  PIN rw0_rd_out[95]
    DIRECTION OUTPUT ;
    USE SIGNAL ;
    SHAPE ABUTMENT ;
    PORT
      LAYER M4 ;
      RECT 0 68.88 0.024 68.904 ;
    END
  END rw0_rd_out[95]
  PIN rw0_rd_out[96]
    DIRECTION OUTPUT ;
    USE SIGNAL ;
    SHAPE ABUTMENT ;
    PORT
      LAYER M4 ;
      RECT 0 69.168 0.024 69.192 ;
    END
  END rw0_rd_out[96]
  PIN rw0_rd_out[97]
    DIRECTION OUTPUT ;
    USE SIGNAL ;
    SHAPE ABUTMENT ;
    PORT
      LAYER M4 ;
      RECT 0 69.456 0.024 69.48 ;
    END
  END rw0_rd_out[97]
  PIN rw0_rd_out[98]
    DIRECTION OUTPUT ;
    USE SIGNAL ;
    SHAPE ABUTMENT ;
    PORT
      LAYER M4 ;
      RECT 0 69.744 0.024 69.768 ;
    END
  END rw0_rd_out[98]
  PIN rw0_rd_out[99]
    DIRECTION OUTPUT ;
    USE SIGNAL ;
    SHAPE ABUTMENT ;
    PORT
      LAYER M4 ;
      RECT 0 70.032 0.024 70.056 ;
    END
  END rw0_rd_out[99]
  PIN rw0_rd_out[100]
    DIRECTION OUTPUT ;
    USE SIGNAL ;
    SHAPE ABUTMENT ;
    PORT
      LAYER M4 ;
      RECT 0 70.32 0.024 70.344 ;
    END
  END rw0_rd_out[100]
  PIN rw0_rd_out[101]
    DIRECTION OUTPUT ;
    USE SIGNAL ;
    SHAPE ABUTMENT ;
    PORT
      LAYER M4 ;
      RECT 0 70.608 0.024 70.632 ;
    END
  END rw0_rd_out[101]
  PIN rw0_rd_out[102]
    DIRECTION OUTPUT ;
    USE SIGNAL ;
    SHAPE ABUTMENT ;
    PORT
      LAYER M4 ;
      RECT 0 70.896 0.024 70.92 ;
    END
  END rw0_rd_out[102]
  PIN rw0_rd_out[103]
    DIRECTION OUTPUT ;
    USE SIGNAL ;
    SHAPE ABUTMENT ;
    PORT
      LAYER M4 ;
      RECT 0 71.184 0.024 71.208 ;
    END
  END rw0_rd_out[103]
  PIN rw0_rd_out[104]
    DIRECTION OUTPUT ;
    USE SIGNAL ;
    SHAPE ABUTMENT ;
    PORT
      LAYER M4 ;
      RECT 0 71.472 0.024 71.496 ;
    END
  END rw0_rd_out[104]
  PIN rw0_rd_out[105]
    DIRECTION OUTPUT ;
    USE SIGNAL ;
    SHAPE ABUTMENT ;
    PORT
      LAYER M4 ;
      RECT 0 71.76 0.024 71.784 ;
    END
  END rw0_rd_out[105]
  PIN rw0_rd_out[106]
    DIRECTION OUTPUT ;
    USE SIGNAL ;
    SHAPE ABUTMENT ;
    PORT
      LAYER M4 ;
      RECT 0 72.048 0.024 72.072 ;
    END
  END rw0_rd_out[106]
  PIN rw0_rd_out[107]
    DIRECTION OUTPUT ;
    USE SIGNAL ;
    SHAPE ABUTMENT ;
    PORT
      LAYER M4 ;
      RECT 0 72.336 0.024 72.36 ;
    END
  END rw0_rd_out[107]
  PIN rw0_rd_out[108]
    DIRECTION OUTPUT ;
    USE SIGNAL ;
    SHAPE ABUTMENT ;
    PORT
      LAYER M4 ;
      RECT 0 72.624 0.024 72.648 ;
    END
  END rw0_rd_out[108]
  PIN rw0_rd_out[109]
    DIRECTION OUTPUT ;
    USE SIGNAL ;
    SHAPE ABUTMENT ;
    PORT
      LAYER M4 ;
      RECT 0 72.912 0.024 72.936 ;
    END
  END rw0_rd_out[109]
  PIN rw0_rd_out[110]
    DIRECTION OUTPUT ;
    USE SIGNAL ;
    SHAPE ABUTMENT ;
    PORT
      LAYER M4 ;
      RECT 0 73.2 0.024 73.224 ;
    END
  END rw0_rd_out[110]
  PIN rw0_rd_out[111]
    DIRECTION OUTPUT ;
    USE SIGNAL ;
    SHAPE ABUTMENT ;
    PORT
      LAYER M4 ;
      RECT 0 73.488 0.024 73.512 ;
    END
  END rw0_rd_out[111]
  PIN rw0_rd_out[112]
    DIRECTION OUTPUT ;
    USE SIGNAL ;
    SHAPE ABUTMENT ;
    PORT
      LAYER M4 ;
      RECT 0 73.776 0.024 73.8 ;
    END
  END rw0_rd_out[112]
  PIN rw0_rd_out[113]
    DIRECTION OUTPUT ;
    USE SIGNAL ;
    SHAPE ABUTMENT ;
    PORT
      LAYER M4 ;
      RECT 0 74.064 0.024 74.088 ;
    END
  END rw0_rd_out[113]
  PIN rw0_rd_out[114]
    DIRECTION OUTPUT ;
    USE SIGNAL ;
    SHAPE ABUTMENT ;
    PORT
      LAYER M4 ;
      RECT 0 74.352 0.024 74.376 ;
    END
  END rw0_rd_out[114]
  PIN rw0_rd_out[115]
    DIRECTION OUTPUT ;
    USE SIGNAL ;
    SHAPE ABUTMENT ;
    PORT
      LAYER M4 ;
      RECT 0 74.64 0.024 74.664 ;
    END
  END rw0_rd_out[115]
  PIN rw0_rd_out[116]
    DIRECTION OUTPUT ;
    USE SIGNAL ;
    SHAPE ABUTMENT ;
    PORT
      LAYER M4 ;
      RECT 0 74.928 0.024 74.952 ;
    END
  END rw0_rd_out[116]
  PIN rw0_rd_out[117]
    DIRECTION OUTPUT ;
    USE SIGNAL ;
    SHAPE ABUTMENT ;
    PORT
      LAYER M4 ;
      RECT 0 75.216 0.024 75.24 ;
    END
  END rw0_rd_out[117]
  PIN rw0_rd_out[118]
    DIRECTION OUTPUT ;
    USE SIGNAL ;
    SHAPE ABUTMENT ;
    PORT
      LAYER M4 ;
      RECT 0 75.504 0.024 75.528 ;
    END
  END rw0_rd_out[118]
  PIN rw0_rd_out[119]
    DIRECTION OUTPUT ;
    USE SIGNAL ;
    SHAPE ABUTMENT ;
    PORT
      LAYER M4 ;
      RECT 0 75.792 0.024 75.816 ;
    END
  END rw0_rd_out[119]
  PIN rw0_rd_out[120]
    DIRECTION OUTPUT ;
    USE SIGNAL ;
    SHAPE ABUTMENT ;
    PORT
      LAYER M4 ;
      RECT 0 76.08 0.024 76.104 ;
    END
  END rw0_rd_out[120]
  PIN rw0_rd_out[121]
    DIRECTION OUTPUT ;
    USE SIGNAL ;
    SHAPE ABUTMENT ;
    PORT
      LAYER M4 ;
      RECT 0 76.368 0.024 76.392 ;
    END
  END rw0_rd_out[121]
  PIN rw0_rd_out[122]
    DIRECTION OUTPUT ;
    USE SIGNAL ;
    SHAPE ABUTMENT ;
    PORT
      LAYER M4 ;
      RECT 0 76.656 0.024 76.68 ;
    END
  END rw0_rd_out[122]
  PIN rw0_rd_out[123]
    DIRECTION OUTPUT ;
    USE SIGNAL ;
    SHAPE ABUTMENT ;
    PORT
      LAYER M4 ;
      RECT 0 76.944 0.024 76.968 ;
    END
  END rw0_rd_out[123]
  PIN rw0_rd_out[124]
    DIRECTION OUTPUT ;
    USE SIGNAL ;
    SHAPE ABUTMENT ;
    PORT
      LAYER M4 ;
      RECT 0 77.232 0.024 77.256 ;
    END
  END rw0_rd_out[124]
  PIN rw0_rd_out[125]
    DIRECTION OUTPUT ;
    USE SIGNAL ;
    SHAPE ABUTMENT ;
    PORT
      LAYER M4 ;
      RECT 0 77.52 0.024 77.544 ;
    END
  END rw0_rd_out[125]
  PIN rw0_rd_out[126]
    DIRECTION OUTPUT ;
    USE SIGNAL ;
    SHAPE ABUTMENT ;
    PORT
      LAYER M4 ;
      RECT 0 77.808 0.024 77.832 ;
    END
  END rw0_rd_out[126]
  PIN rw0_rd_out[127]
    DIRECTION OUTPUT ;
    USE SIGNAL ;
    SHAPE ABUTMENT ;
    PORT
      LAYER M4 ;
      RECT 0 78.096 0.024 78.12 ;
    END
  END rw0_rd_out[127]
  PIN rw0_rd_out[128]
    DIRECTION OUTPUT ;
    USE SIGNAL ;
    SHAPE ABUTMENT ;
    PORT
      LAYER M4 ;
      RECT 0 78.384 0.024 78.408 ;
    END
  END rw0_rd_out[128]
  PIN rw0_rd_out[129]
    DIRECTION OUTPUT ;
    USE SIGNAL ;
    SHAPE ABUTMENT ;
    PORT
      LAYER M4 ;
      RECT 0 78.672 0.024 78.696 ;
    END
  END rw0_rd_out[129]
  PIN rw0_rd_out[130]
    DIRECTION OUTPUT ;
    USE SIGNAL ;
    SHAPE ABUTMENT ;
    PORT
      LAYER M4 ;
      RECT 0 78.96 0.024 78.984 ;
    END
  END rw0_rd_out[130]
  PIN rw0_rd_out[131]
    DIRECTION OUTPUT ;
    USE SIGNAL ;
    SHAPE ABUTMENT ;
    PORT
      LAYER M4 ;
      RECT 0 79.248 0.024 79.272 ;
    END
  END rw0_rd_out[131]
  PIN rw0_rd_out[132]
    DIRECTION OUTPUT ;
    USE SIGNAL ;
    SHAPE ABUTMENT ;
    PORT
      LAYER M4 ;
      RECT 0 79.536 0.024 79.56 ;
    END
  END rw0_rd_out[132]
  PIN rw0_rd_out[133]
    DIRECTION OUTPUT ;
    USE SIGNAL ;
    SHAPE ABUTMENT ;
    PORT
      LAYER M4 ;
      RECT 0 79.824 0.024 79.848 ;
    END
  END rw0_rd_out[133]
  PIN rw0_rd_out[134]
    DIRECTION OUTPUT ;
    USE SIGNAL ;
    SHAPE ABUTMENT ;
    PORT
      LAYER M4 ;
      RECT 0 80.112 0.024 80.136 ;
    END
  END rw0_rd_out[134]
  PIN rw0_rd_out[135]
    DIRECTION OUTPUT ;
    USE SIGNAL ;
    SHAPE ABUTMENT ;
    PORT
      LAYER M4 ;
      RECT 0 80.4 0.024 80.424 ;
    END
  END rw0_rd_out[135]
  PIN rw0_addr_in[0]
    DIRECTION INPUT ;
    USE SIGNAL ;
    SHAPE ABUTMENT ;
    PORT
      LAYER M4 ;
      RECT 0 80.688 0.024 80.712 ;
    END
  END rw0_addr_in[0]
  PIN rw0_addr_in[1]
    DIRECTION INPUT ;
    USE SIGNAL ;
    SHAPE ABUTMENT ;
    PORT
      LAYER M4 ;
      RECT 0 80.976 0.024 81 ;
    END
  END rw0_addr_in[1]
  PIN rw0_addr_in[2]
    DIRECTION INPUT ;
    USE SIGNAL ;
    SHAPE ABUTMENT ;
    PORT
      LAYER M4 ;
      RECT 0 81.264 0.024 81.288 ;
    END
  END rw0_addr_in[2]
  PIN rw0_addr_in[3]
    DIRECTION INPUT ;
    USE SIGNAL ;
    SHAPE ABUTMENT ;
    PORT
      LAYER M4 ;
      RECT 0 81.552 0.024 81.576 ;
    END
  END rw0_addr_in[3]
  PIN rw0_addr_in[4]
    DIRECTION INPUT ;
    USE SIGNAL ;
    SHAPE ABUTMENT ;
    PORT
      LAYER M4 ;
      RECT 0 81.84 0.024 81.864 ;
    END
  END rw0_addr_in[4]
  PIN rw0_addr_in[5]
    DIRECTION INPUT ;
    USE SIGNAL ;
    SHAPE ABUTMENT ;
    PORT
      LAYER M4 ;
      RECT 0 82.128 0.024 82.152 ;
    END
  END rw0_addr_in[5]
  PIN rw0_addr_in[6]
    DIRECTION INPUT ;
    USE SIGNAL ;
    SHAPE ABUTMENT ;
    PORT
      LAYER M4 ;
      RECT 0 82.416 0.024 82.44 ;
    END
  END rw0_addr_in[6]
  PIN rw0_addr_in[7]
    DIRECTION INPUT ;
    USE SIGNAL ;
    SHAPE ABUTMENT ;
    PORT
      LAYER M4 ;
      RECT 0 82.704 0.024 82.728 ;
    END
  END rw0_addr_in[7]
  PIN rw0_addr_in[8]
    DIRECTION INPUT ;
    USE SIGNAL ;
    SHAPE ABUTMENT ;
    PORT
      LAYER M4 ;
      RECT 0 82.992 0.024 83.016 ;
    END
  END rw0_addr_in[8]
  PIN rw0_addr_in[9]
    DIRECTION INPUT ;
    USE SIGNAL ;
    SHAPE ABUTMENT ;
    PORT
      LAYER M4 ;
      RECT 0 83.28 0.024 83.304 ;
    END
  END rw0_addr_in[9]
  PIN rw0_we_in
    DIRECTION INPUT ;
    USE SIGNAL ;
    SHAPE ABUTMENT ;
    PORT
      LAYER M4 ;
      RECT 0 83.568 0.024 83.592 ;
    END
  END rw0_we_in
  PIN rw0_ce_in
    DIRECTION INPUT ;
    USE SIGNAL ;
    SHAPE ABUTMENT ;
    PORT
      LAYER M4 ;
      RECT 0 83.856 0.024 83.88 ;
    END
  END rw0_ce_in
  PIN rw0_clk
    DIRECTION INPUT ;
    USE SIGNAL ;
    SHAPE ABUTMENT ;
    PORT
      LAYER M4 ;
      RECT 0 84.144 0.024 84.168 ;
    END
  END rw0_clk
  PIN VSS
    DIRECTION INOUT ;
    USE GROUND ;
    PORT
      LAYER M4 ;
      RECT 0.048 0 36.79 0.096 ;
      RECT 0.048 0.768 36.79 0.864 ;
      RECT 0.048 1.536 36.79 1.632 ;
      RECT 0.048 2.304 36.79 2.4 ;
      RECT 0.048 3.072 36.79 3.168 ;
      RECT 0.048 3.84 36.79 3.936 ;
      RECT 0.048 4.608 36.79 4.704 ;
      RECT 0.048 5.376 36.79 5.472 ;
      RECT 0.048 6.144 36.79 6.24 ;
      RECT 0.048 6.912 36.79 7.008 ;
      RECT 0.048 7.68 36.79 7.776 ;
      RECT 0.048 8.448 36.79 8.544 ;
      RECT 0.048 9.216 36.79 9.312 ;
      RECT 0.048 9.984 36.79 10.08 ;
      RECT 0.048 10.752 36.79 10.848 ;
      RECT 0.048 11.52 36.79 11.616 ;
      RECT 0.048 12.288 36.79 12.384 ;
      RECT 0.048 13.056 36.79 13.152 ;
      RECT 0.048 13.824 36.79 13.92 ;
      RECT 0.048 14.592 36.79 14.688 ;
      RECT 0.048 15.36 36.79 15.456 ;
      RECT 0.048 16.128 36.79 16.224 ;
      RECT 0.048 16.896 36.79 16.992 ;
      RECT 0.048 17.664 36.79 17.76 ;
      RECT 0.048 18.432 36.79 18.528 ;
      RECT 0.048 19.2 36.79 19.296 ;
      RECT 0.048 19.968 36.79 20.064 ;
      RECT 0.048 20.736 36.79 20.832 ;
      RECT 0.048 21.504 36.79 21.6 ;
      RECT 0.048 22.272 36.79 22.368 ;
      RECT 0.048 23.04 36.79 23.136 ;
      RECT 0.048 23.808 36.79 23.904 ;
      RECT 0.048 24.576 36.79 24.672 ;
      RECT 0.048 25.344 36.79 25.44 ;
      RECT 0.048 26.112 36.79 26.208 ;
      RECT 0.048 26.88 36.79 26.976 ;
      RECT 0.048 27.648 36.79 27.744 ;
      RECT 0.048 28.416 36.79 28.512 ;
      RECT 0.048 29.184 36.79 29.28 ;
      RECT 0.048 29.952 36.79 30.048 ;
      RECT 0.048 30.72 36.79 30.816 ;
      RECT 0.048 31.488 36.79 31.584 ;
      RECT 0.048 32.256 36.79 32.352 ;
      RECT 0.048 33.024 36.79 33.12 ;
      RECT 0.048 33.792 36.79 33.888 ;
      RECT 0.048 34.56 36.79 34.656 ;
      RECT 0.048 35.328 36.79 35.424 ;
      RECT 0.048 36.096 36.79 36.192 ;
      RECT 0.048 36.864 36.79 36.96 ;
      RECT 0.048 37.632 36.79 37.728 ;
      RECT 0.048 38.4 36.79 38.496 ;
      RECT 0.048 39.168 36.79 39.264 ;
      RECT 0.048 39.936 36.79 40.032 ;
      RECT 0.048 40.704 36.79 40.8 ;
      RECT 0.048 41.472 36.79 41.568 ;
      RECT 0.048 42.24 36.79 42.336 ;
      RECT 0.048 43.008 36.79 43.104 ;
      RECT 0.048 43.776 36.79 43.872 ;
      RECT 0.048 44.544 36.79 44.64 ;
      RECT 0.048 45.312 36.79 45.408 ;
      RECT 0.048 46.08 36.79 46.176 ;
      RECT 0.048 46.848 36.79 46.944 ;
      RECT 0.048 47.616 36.79 47.712 ;
      RECT 0.048 48.384 36.79 48.48 ;
      RECT 0.048 49.152 36.79 49.248 ;
      RECT 0.048 49.92 36.79 50.016 ;
      RECT 0.048 50.688 36.79 50.784 ;
      RECT 0.048 51.456 36.79 51.552 ;
      RECT 0.048 52.224 36.79 52.32 ;
      RECT 0.048 52.992 36.79 53.088 ;
      RECT 0.048 53.76 36.79 53.856 ;
      RECT 0.048 54.528 36.79 54.624 ;
      RECT 0.048 55.296 36.79 55.392 ;
      RECT 0.048 56.064 36.79 56.16 ;
      RECT 0.048 56.832 36.79 56.928 ;
      RECT 0.048 57.6 36.79 57.696 ;
      RECT 0.048 58.368 36.79 58.464 ;
      RECT 0.048 59.136 36.79 59.232 ;
      RECT 0.048 59.904 36.79 60 ;
      RECT 0.048 60.672 36.79 60.768 ;
      RECT 0.048 61.44 36.79 61.536 ;
      RECT 0.048 62.208 36.79 62.304 ;
      RECT 0.048 62.976 36.79 63.072 ;
      RECT 0.048 63.744 36.79 63.84 ;
      RECT 0.048 64.512 36.79 64.608 ;
      RECT 0.048 65.28 36.79 65.376 ;
      RECT 0.048 66.048 36.79 66.144 ;
      RECT 0.048 66.816 36.79 66.912 ;
      RECT 0.048 67.584 36.79 67.68 ;
      RECT 0.048 68.352 36.79 68.448 ;
      RECT 0.048 69.12 36.79 69.216 ;
      RECT 0.048 69.888 36.79 69.984 ;
      RECT 0.048 70.656 36.79 70.752 ;
      RECT 0.048 71.424 36.79 71.52 ;
      RECT 0.048 72.192 36.79 72.288 ;
      RECT 0.048 72.96 36.79 73.056 ;
      RECT 0.048 73.728 36.79 73.824 ;
      RECT 0.048 74.496 36.79 74.592 ;
      RECT 0.048 75.264 36.79 75.36 ;
      RECT 0.048 76.032 36.79 76.128 ;
      RECT 0.048 76.8 36.79 76.896 ;
      RECT 0.048 77.568 36.79 77.664 ;
      RECT 0.048 78.336 36.79 78.432 ;
      RECT 0.048 79.104 36.79 79.2 ;
      RECT 0.048 79.872 36.79 79.968 ;
      RECT 0.048 80.64 36.79 80.736 ;
      RECT 0.048 81.408 36.79 81.504 ;
      RECT 0.048 82.176 36.79 82.272 ;
      RECT 0.048 82.944 36.79 83.04 ;
      RECT 0.048 83.712 36.79 83.808 ;
      RECT 0.048 84.48 36.79 84.576 ;
      RECT 0.048 85.248 36.79 85.344 ;
      RECT 0.048 86.016 36.79 86.112 ;
      RECT 0.048 86.784 36.79 86.88 ;
      RECT 0.048 87.552 36.79 87.648 ;
      RECT 0.048 88.32 36.79 88.416 ;
      RECT 0.048 89.088 36.79 89.184 ;
      RECT 0.048 89.856 36.79 89.952 ;
      RECT 0.048 90.624 36.79 90.72 ;
      RECT 0.048 91.392 36.79 91.488 ;
      RECT 0.048 92.16 36.79 92.256 ;
    END
  END VSS
  PIN VDD
    DIRECTION INOUT ;
    USE POWER ;
    PORT
      LAYER M4 ;
      RECT 0.048 0.384 36.79 0.48 ;
      RECT 0.048 1.152 36.79 1.248 ;
      RECT 0.048 1.92 36.79 2.016 ;
      RECT 0.048 2.688 36.79 2.784 ;
      RECT 0.048 3.456 36.79 3.552 ;
      RECT 0.048 4.224 36.79 4.32 ;
      RECT 0.048 4.992 36.79 5.088 ;
      RECT 0.048 5.76 36.79 5.856 ;
      RECT 0.048 6.528 36.79 6.624 ;
      RECT 0.048 7.296 36.79 7.392 ;
      RECT 0.048 8.064 36.79 8.16 ;
      RECT 0.048 8.832 36.79 8.928 ;
      RECT 0.048 9.6 36.79 9.696 ;
      RECT 0.048 10.368 36.79 10.464 ;
      RECT 0.048 11.136 36.79 11.232 ;
      RECT 0.048 11.904 36.79 12 ;
      RECT 0.048 12.672 36.79 12.768 ;
      RECT 0.048 13.44 36.79 13.536 ;
      RECT 0.048 14.208 36.79 14.304 ;
      RECT 0.048 14.976 36.79 15.072 ;
      RECT 0.048 15.744 36.79 15.84 ;
      RECT 0.048 16.512 36.79 16.608 ;
      RECT 0.048 17.28 36.79 17.376 ;
      RECT 0.048 18.048 36.79 18.144 ;
      RECT 0.048 18.816 36.79 18.912 ;
      RECT 0.048 19.584 36.79 19.68 ;
      RECT 0.048 20.352 36.79 20.448 ;
      RECT 0.048 21.12 36.79 21.216 ;
      RECT 0.048 21.888 36.79 21.984 ;
      RECT 0.048 22.656 36.79 22.752 ;
      RECT 0.048 23.424 36.79 23.52 ;
      RECT 0.048 24.192 36.79 24.288 ;
      RECT 0.048 24.96 36.79 25.056 ;
      RECT 0.048 25.728 36.79 25.824 ;
      RECT 0.048 26.496 36.79 26.592 ;
      RECT 0.048 27.264 36.79 27.36 ;
      RECT 0.048 28.032 36.79 28.128 ;
      RECT 0.048 28.8 36.79 28.896 ;
      RECT 0.048 29.568 36.79 29.664 ;
      RECT 0.048 30.336 36.79 30.432 ;
      RECT 0.048 31.104 36.79 31.2 ;
      RECT 0.048 31.872 36.79 31.968 ;
      RECT 0.048 32.64 36.79 32.736 ;
      RECT 0.048 33.408 36.79 33.504 ;
      RECT 0.048 34.176 36.79 34.272 ;
      RECT 0.048 34.944 36.79 35.04 ;
      RECT 0.048 35.712 36.79 35.808 ;
      RECT 0.048 36.48 36.79 36.576 ;
      RECT 0.048 37.248 36.79 37.344 ;
      RECT 0.048 38.016 36.79 38.112 ;
      RECT 0.048 38.784 36.79 38.88 ;
      RECT 0.048 39.552 36.79 39.648 ;
      RECT 0.048 40.32 36.79 40.416 ;
      RECT 0.048 41.088 36.79 41.184 ;
      RECT 0.048 41.856 36.79 41.952 ;
      RECT 0.048 42.624 36.79 42.72 ;
      RECT 0.048 43.392 36.79 43.488 ;
      RECT 0.048 44.16 36.79 44.256 ;
      RECT 0.048 44.928 36.79 45.024 ;
      RECT 0.048 45.696 36.79 45.792 ;
      RECT 0.048 46.464 36.79 46.56 ;
      RECT 0.048 47.232 36.79 47.328 ;
      RECT 0.048 48 36.79 48.096 ;
      RECT 0.048 48.768 36.79 48.864 ;
      RECT 0.048 49.536 36.79 49.632 ;
      RECT 0.048 50.304 36.79 50.4 ;
      RECT 0.048 51.072 36.79 51.168 ;
      RECT 0.048 51.84 36.79 51.936 ;
      RECT 0.048 52.608 36.79 52.704 ;
      RECT 0.048 53.376 36.79 53.472 ;
      RECT 0.048 54.144 36.79 54.24 ;
      RECT 0.048 54.912 36.79 55.008 ;
      RECT 0.048 55.68 36.79 55.776 ;
      RECT 0.048 56.448 36.79 56.544 ;
      RECT 0.048 57.216 36.79 57.312 ;
      RECT 0.048 57.984 36.79 58.08 ;
      RECT 0.048 58.752 36.79 58.848 ;
      RECT 0.048 59.52 36.79 59.616 ;
      RECT 0.048 60.288 36.79 60.384 ;
      RECT 0.048 61.056 36.79 61.152 ;
      RECT 0.048 61.824 36.79 61.92 ;
      RECT 0.048 62.592 36.79 62.688 ;
      RECT 0.048 63.36 36.79 63.456 ;
      RECT 0.048 64.128 36.79 64.224 ;
      RECT 0.048 64.896 36.79 64.992 ;
      RECT 0.048 65.664 36.79 65.76 ;
      RECT 0.048 66.432 36.79 66.528 ;
      RECT 0.048 67.2 36.79 67.296 ;
      RECT 0.048 67.968 36.79 68.064 ;
      RECT 0.048 68.736 36.79 68.832 ;
      RECT 0.048 69.504 36.79 69.6 ;
      RECT 0.048 70.272 36.79 70.368 ;
      RECT 0.048 71.04 36.79 71.136 ;
      RECT 0.048 71.808 36.79 71.904 ;
      RECT 0.048 72.576 36.79 72.672 ;
      RECT 0.048 73.344 36.79 73.44 ;
      RECT 0.048 74.112 36.79 74.208 ;
      RECT 0.048 74.88 36.79 74.976 ;
      RECT 0.048 75.648 36.79 75.744 ;
      RECT 0.048 76.416 36.79 76.512 ;
      RECT 0.048 77.184 36.79 77.28 ;
      RECT 0.048 77.952 36.79 78.048 ;
      RECT 0.048 78.72 36.79 78.816 ;
      RECT 0.048 79.488 36.79 79.584 ;
      RECT 0.048 80.256 36.79 80.352 ;
      RECT 0.048 81.024 36.79 81.12 ;
      RECT 0.048 81.792 36.79 81.888 ;
      RECT 0.048 82.56 36.79 82.656 ;
      RECT 0.048 83.328 36.79 83.424 ;
      RECT 0.048 84.096 36.79 84.192 ;
      RECT 0.048 84.864 36.79 84.96 ;
      RECT 0.048 85.632 36.79 85.728 ;
      RECT 0.048 86.4 36.79 86.496 ;
      RECT 0.048 87.168 36.79 87.264 ;
      RECT 0.048 87.936 36.79 88.032 ;
      RECT 0.048 88.704 36.79 88.8 ;
      RECT 0.048 89.472 36.79 89.568 ;
      RECT 0.048 90.24 36.79 90.336 ;
      RECT 0.048 91.008 36.79 91.104 ;
      RECT 0.048 91.776 36.79 91.872 ;
    END
  END VDD
  OBS
    LAYER M1 ;
    RECT 0 0 36.838 92.433 ;
    LAYER M2 ;
    RECT 0 0 36.838 92.433 ;
    LAYER M3 ;
    RECT 0 0 36.838 92.433 ;
  END
END ht_asap7_rocketgemmini_cc_dir_ext

END LIBRARY
